(* Logix 5000 AddOnInstructionDefinition export POINT_DEC; software revision 30.00; part 2 of 3 *)

ADD_ON_INSTRUCTION B256_ADJ   (* revision 1.0 20170916, vendor Kenneth A. Fischer *)
// if c >= m then subtract m
// Revision note:
// Rev1.0: 20170916 - Initial Release
VAR_IN_OUT
   Inp_C : DINT[22]; {required}
END_VAR
VAR
   i : INT;
   j : INT;
END_VAR

ROUTINE Logic   (* ladder *)
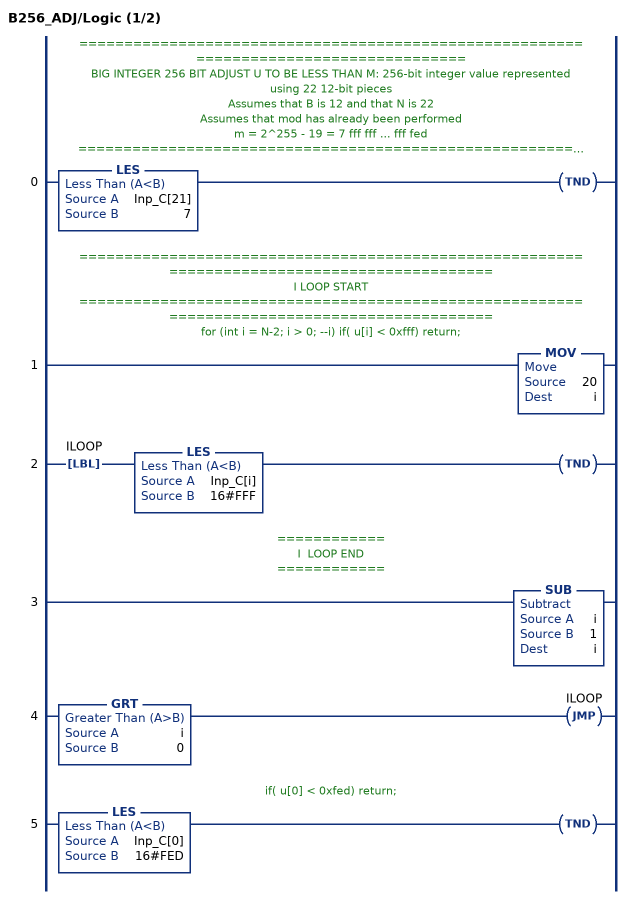
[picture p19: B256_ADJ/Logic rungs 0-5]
   // ======================================================================================
   // BIG INTEGER 256 BIT ADJUST U TO BE LESS THAN M: 256-bit integer value represented using 22 12-bit pieces
   // Assumes that B is 12 and that N is 22
   // Assumes that mod has already been performed
   // m = 2^255 - 19 = 7 fff fff ... fff fed
   // ======================================================================================
   // if (u[n-1] < 7) return;
   0: LES(Inp_C[21],7)TND();
   // ============================================================================================
   // I LOOP START
   // ============================================================================================
   // for (int i = N-2; i > 0; --i) if( u[i] < 0xfff) return;
   1: MOV(20,i);
   2: LBL(ILOOP)LES(Inp_C[i],16#FFF)TND();
   // ============
   // I  LOOP END
   // ============
   3: SUB(i,1,i);
   4: GRT(i,0)JMP(ILOOP);
   // if( u[0] < 0xfed) return;
   5: LES(Inp_C[0],16#FED)TND();
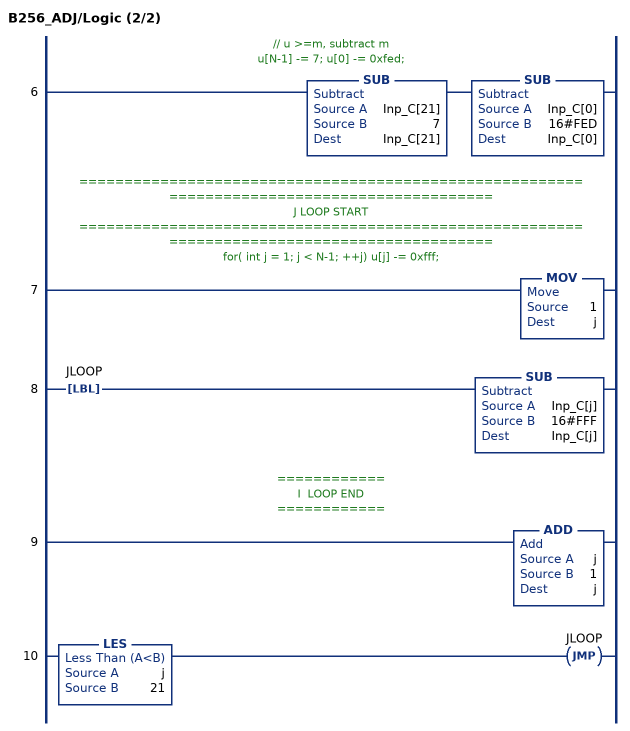
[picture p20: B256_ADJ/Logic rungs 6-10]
   // // u >=m, subtract m
   // u[N-1] -= 7; u[0] -= 0xfed;
   6: SUB(Inp_C[21],7,Inp_C[21])SUB(Inp_C[0],16#FED,Inp_C[0]);
   // ============================================================================================
   // J LOOP START
   // ============================================================================================
   // for( int j = 1; j < N-1; ++j) u[j] -= 0xfff;
   7: MOV(1,j);
   8: LBL(JLOOP)SUB(Inp_C[j],16#FFF,Inp_C[j]);
   // ============
   // I  LOOP END
   // ============
   9: ADD(j,1,j);
   10: LES(j,21)JMP(JLOOP);
END_ROUTINE
END_ADD_ON_INSTRUCTION

ADD_ON_INSTRUCTION B256_CtoE   (* revision 1.0 20170916, vendor Kenneth A. Fischer *)
// Convert 256-bit value using 22 12-bit pieces into 256-bit value using 32 8-bit pieces
// Revision note:
// Rev1.0: 20170916 - Initial Release
VAR_IN_OUT
   Inp_C : DINT[22]; {required}
   Out_E : DINT[32]; {required}
END_VAR
VAR
   i : INT;
   j : INT;
   TEMP1 : DINT;
   TEMP2 : DINT;
   D_SHL : D_SHL;
   D_SHR : D_SHR;
END_VAR

ROUTINE Logic   (* ladder *)
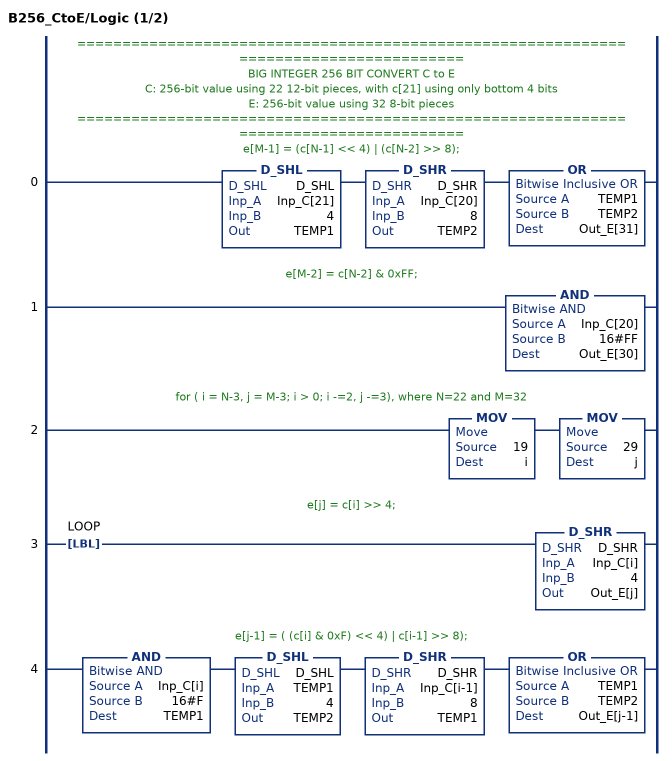
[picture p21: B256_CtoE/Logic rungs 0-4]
   // ======================================================================================
   // BIG INTEGER 256 BIT CONVERT C to E
   // C: 256-bit value using 22 12-bit pieces, with c[21] using only bottom 4 bits
   // E: 256-bit value using 32 8-bit pieces
   // ======================================================================================
   // e[M-1] = (c[N-1] << 4) | (c[N-2] >> 8);
   0: D_SHL(D_SHL,Inp_C[21],4,TEMP1)D_SHR(D_SHR,Inp_C[20],8,TEMP2)OR(TEMP1,TEMP2,Out_E[31]);
   // e[M-2] = c[N-2] & 0xFF;
   1: AND(Inp_C[20],16#FF,Out_E[30]);
   // for ( i = N-3, j = M-3; i > 0; i -=2, j -=3), where N=22 and M=32
   2: MOV(19,i)MOV(29,j);
   // e[j] = c[i] >> 4;
   3: LBL(LOOP)D_SHR(D_SHR,Inp_C[i],4,Out_E[j]);
   // e[j-1] = ( (c[i] & 0xF) << 4) | c[i-1] >> 8);
   4: AND(Inp_C[i],16#F,TEMP1)D_SHL(D_SHL,TEMP1,4,TEMP2)D_SHR(D_SHR,Inp_C[i-1],8,TEMP1)OR(TEMP1,TEMP2,Out_E[j-1]);
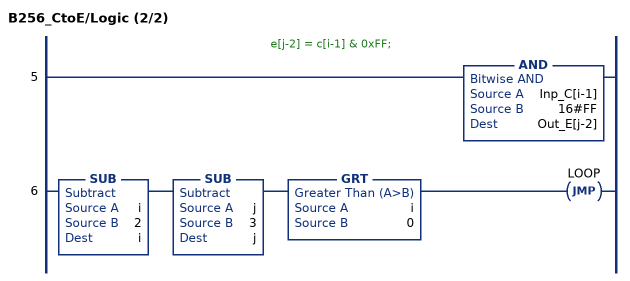
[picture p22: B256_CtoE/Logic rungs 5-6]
   // e[j-2] = c[i-1] & 0xFF;
   5: AND(Inp_C[i-1],16#FF,Out_E[j-2]);
   6: SUB(i,2,i)SUB(j,3,j)GRT(i,0)JMP(LOOP);
END_ROUTINE
END_ADD_ON_INSTRUCTION

ADD_ON_INSTRUCTION B256_EtoC   (* revision 1.0 20170916, vendor Kenneth A. Fischer *)
// Convert 256-bit value using 32 8-bit pieces into 256-bit value using 22 12-bit pieces
// Revision note:
// Rev1.0: 20170916 - Initial Release
VAR_IN_OUT
   Inp_E : DINT[32]; {required}
   Out_C : DINT[22]; {required}
END_VAR
VAR
   i : INT;
   j : INT;
   TEMP1 : DINT;
   TEMP2 : DINT;
   D_SHL : D_SHL;
   D_SHR : D_SHR;
END_VAR

ROUTINE Logic   (* ladder *)
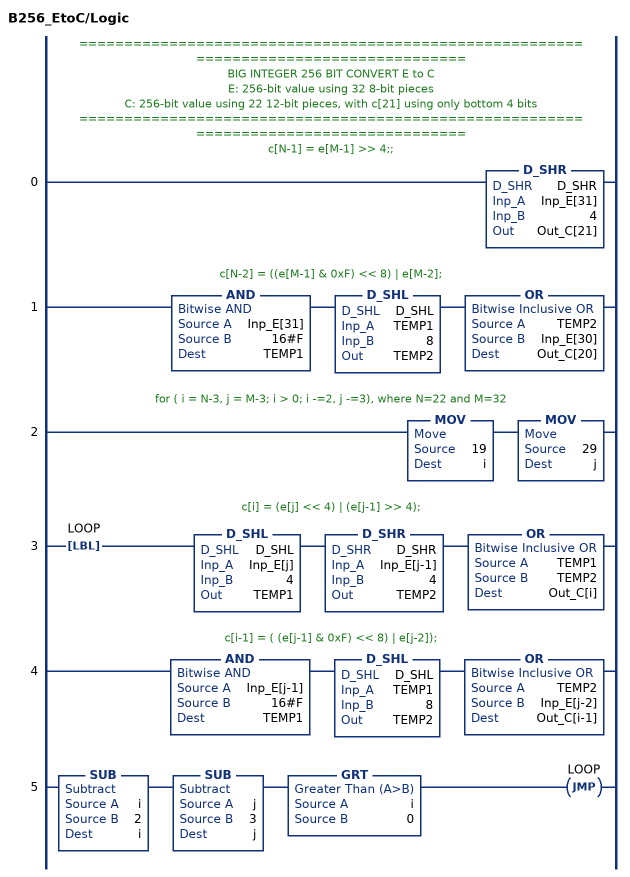
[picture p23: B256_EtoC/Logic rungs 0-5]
   // ======================================================================================
   // BIG INTEGER 256 BIT CONVERT E to C
   // E: 256-bit value using 32 8-bit pieces
   // C: 256-bit value using 22 12-bit pieces, with c[21] using only bottom 4 bits
   // ======================================================================================
   // c[N-1] = e[M-1] >> 4;;
   0: D_SHR(D_SHR,Inp_E[31],4,Out_C[21]);
   // c[N-2] = ((e[M-1] & 0xF) << 8) | e[M-2];
   1: AND(Inp_E[31],16#F,TEMP1)D_SHL(D_SHL,TEMP1,8,TEMP2)OR(TEMP2,Inp_E[30],Out_C[20]);
   // for ( i = N-3, j = M-3; i > 0; i -=2, j -=3), where N=22 and M=32
   2: MOV(19,i)MOV(29,j);
   // c[i] = (e[j] << 4) | (e[j-1] >> 4);
   3: LBL(LOOP)D_SHL(D_SHL,Inp_E[j],4,TEMP1)D_SHR(D_SHR,Inp_E[j-1],4,TEMP2)OR(TEMP1,TEMP2,Out_C[i]);
   // c[i-1] = ( (e[j-1] & 0xF) << 8) | e[j-2]);
   4: AND(Inp_E[j-1],16#F,TEMP1)D_SHL(D_SHL,TEMP1,8,TEMP2)OR(TEMP2,Inp_E[j-2],Out_C[i-1]);
   5: SUB(i,2,i)SUB(j,3,j)GRT(i,0)JMP(LOOP);
END_ROUTINE
END_ADD_ON_INSTRUCTION

ADD_ON_INSTRUCTION B256_COMPARE   (* revision 1.0 20170916, vendor Kenneth A. Fischer *)
// Determines if C1<C2, C1=C2, or C1>C2
// Revision note:
// Rev1.0: 20170916 - Initial Release
VAR_IN_OUT
   Inp_C1 : DINT[22]; {required}
   Inp_C2 : DINT[22]; {required}
END_VAR
VAR_OUTPUT
   EQUAL : BOOL; {access Read Only}
   GREATER : BOOL; {access Read Only}
   LESS : BOOL; {access Read Only}
END_VAR
VAR
   C3 : DINT;
   i : DINT;
END_VAR

ROUTINE Logic   (* ladder *)
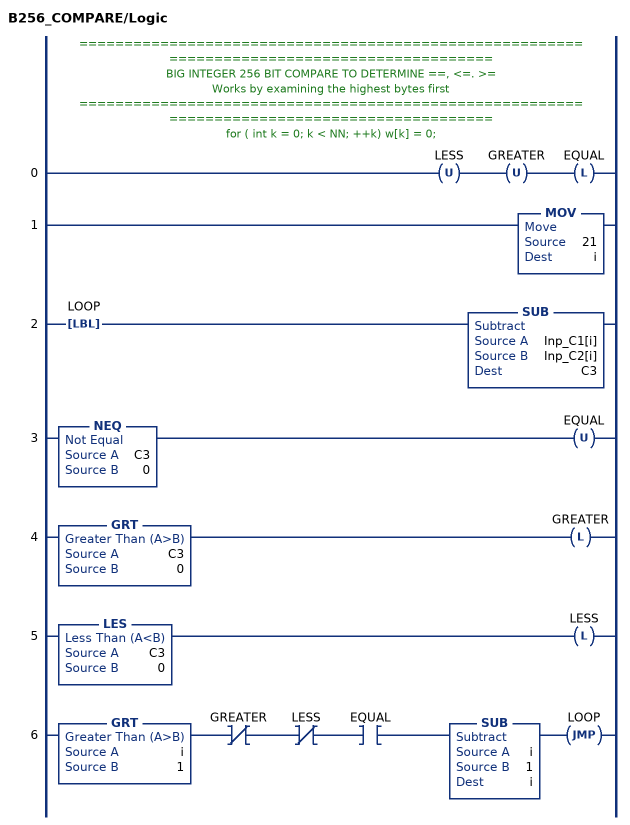
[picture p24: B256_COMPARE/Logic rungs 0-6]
   // ============================================================================================
   // BIG INTEGER 256 BIT COMPARE TO DETERMINE ==, <=. >=
   // Works by examining the highest bytes first
   // ============================================================================================
   // for ( int k = 0; k < NN; ++k) w[k] = 0;
   0: OTU(LESS)OTU(GREATER)OTL(EQUAL);
   1: MOV(21,i);
   2: LBL(LOOP)SUB(Inp_C1[i],Inp_C2[i],C3);
   3: NEQ(C3,0)OTU(EQUAL);
   4: GRT(C3,0)OTL(GREATER);
   5: LES(C3,0)OTL(LESS);
   6: GRT(i,1)XIO(GREATER)XIO(LESS)XIC(EQUAL)SUB(i,1,i)JMP(LOOP);
END_ROUTINE
END_ADD_ON_INSTRUCTION

ADD_ON_INSTRUCTION B256_StoC_LE   (* revision 1.0 20170916, vendor Kenneth A. Fischer *)
// Convert 256-bit value using 64 hex string characters into 256-bit value using 22 12-bit pieces
// Little Endian
// Revision note:
// Rev1.0: 20170916 - Initial Release
VAR_IN_OUT
   Temp_E : DINT[32]; {required}
   Inp_S : STRING; {required}
   Out_C : DINT[22]; {required}
END_VAR
VAR
   byte : DINT[3];
   D_SHL : D_SHL;
   i : INT;
   j : INT;
   k : DINT;
   temp : DINT;
   B256_CtoE : B256_CtoE;
   E : DINT[32];
   B256_EtoC : B256_EtoC;
END_VAR

ROUTINE Logic   (* ladder *)
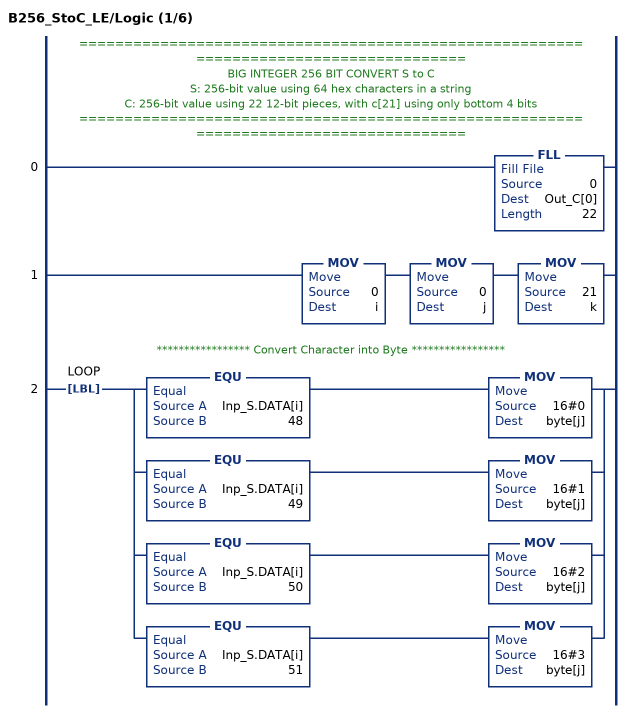
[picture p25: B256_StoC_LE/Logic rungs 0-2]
   // ======================================================================================
   // BIG INTEGER 256 BIT CONVERT S to C
   // S: 256-bit value using 64 hex characters in a string
   // C: 256-bit value using 22 12-bit pieces, with c[21] using only bottom 4 bits
   // ======================================================================================
   0: FLL(0,Out_C[0],22);
   1: MOV(0,i)MOV(0,j)MOV(21,k);
   // ***************** Convert Character into Byte *****************
   2: LBL(LOOP)[EQU(Inp_S.DATA[i],48) MOV(16#0,byte[j]) ,EQU(Inp_S.DATA[i],49) MOV(16#1,byte[j]) ,EQU(Inp_S.DATA[i],50) MOV(16#2,byte[j]) ,EQU(Inp_S.DATA[i],51) MOV(16#3,byte[j]) ];
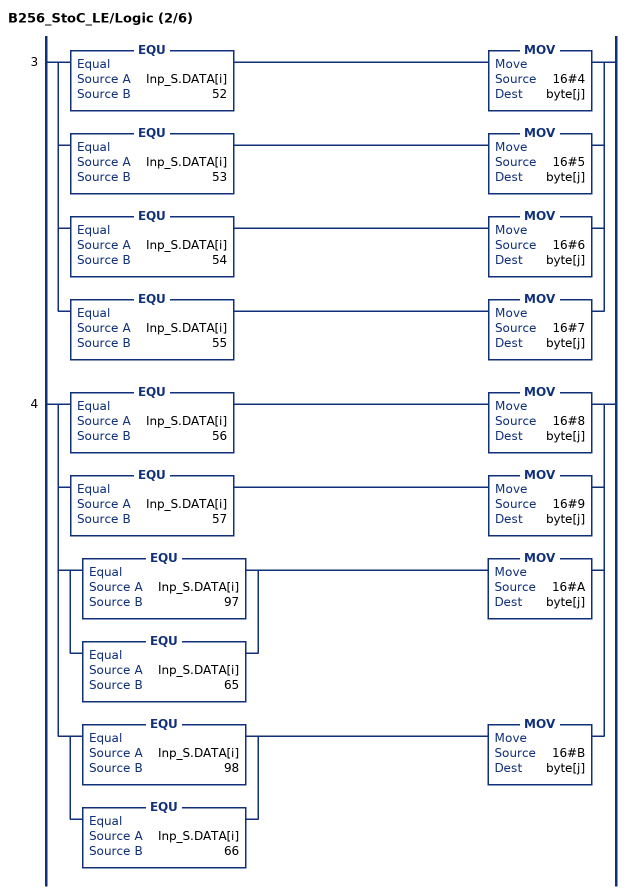
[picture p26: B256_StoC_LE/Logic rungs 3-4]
   3: [EQU(Inp_S.DATA[i],52) MOV(16#4,byte[j]) ,EQU(Inp_S.DATA[i],53) MOV(16#5,byte[j]) ,EQU(Inp_S.DATA[i],54) MOV(16#6,byte[j]) ,EQU(Inp_S.DATA[i],55) MOV(16#7,byte[j]) ];
   4: [EQU(Inp_S.DATA[i],56) MOV(16#8,byte[j]) ,EQU(Inp_S.DATA[i],57) MOV(16#9,byte[j]) ,[EQU(Inp_S.DATA[i],97) ,EQU(Inp_S.DATA[i],65) ] MOV(16#A,byte[j]) ,[EQU(Inp_S.DATA[i],98) ,EQU(Inp_S.DATA[i],66) ] MOV(16#B,byte[j]) ];
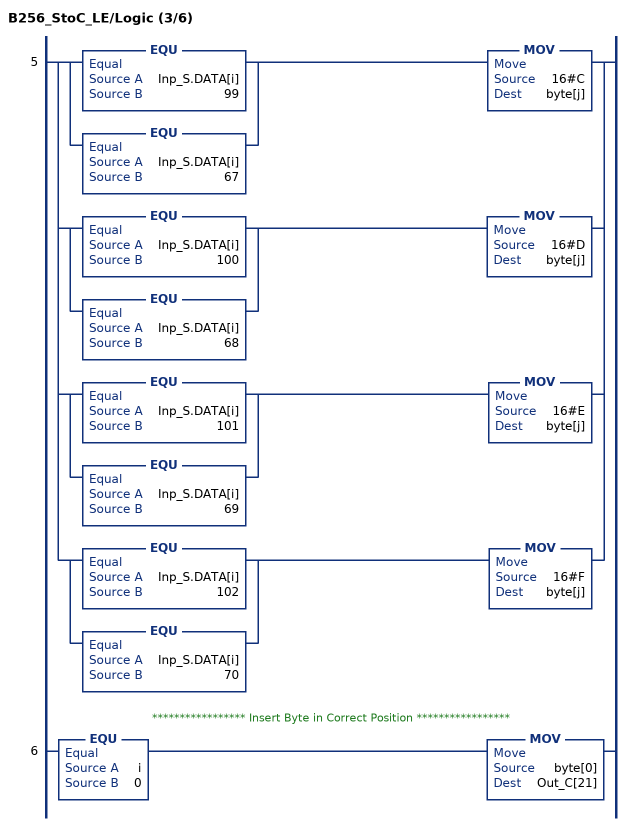
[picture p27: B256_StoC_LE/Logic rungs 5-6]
   5: [[EQU(Inp_S.DATA[i],99) ,EQU(Inp_S.DATA[i],67) ] MOV(16#C,byte[j]) ,[EQU(Inp_S.DATA[i],100) ,EQU(Inp_S.DATA[i],68) ] MOV(16#D,byte[j]) ,[EQU(Inp_S.DATA[i],101) ,EQU(Inp_S.DATA[i],69) ] MOV(16#E,byte[j]) ,[EQU(Inp_S.DATA[i],102) ,EQU(Inp_S.DATA[i],70) ] MOV(16#F,byte[j]) ];
   // ***************** Insert Byte in Correct Position *****************
   6: EQU(i,0)MOV(byte[0],Out_C[21]);
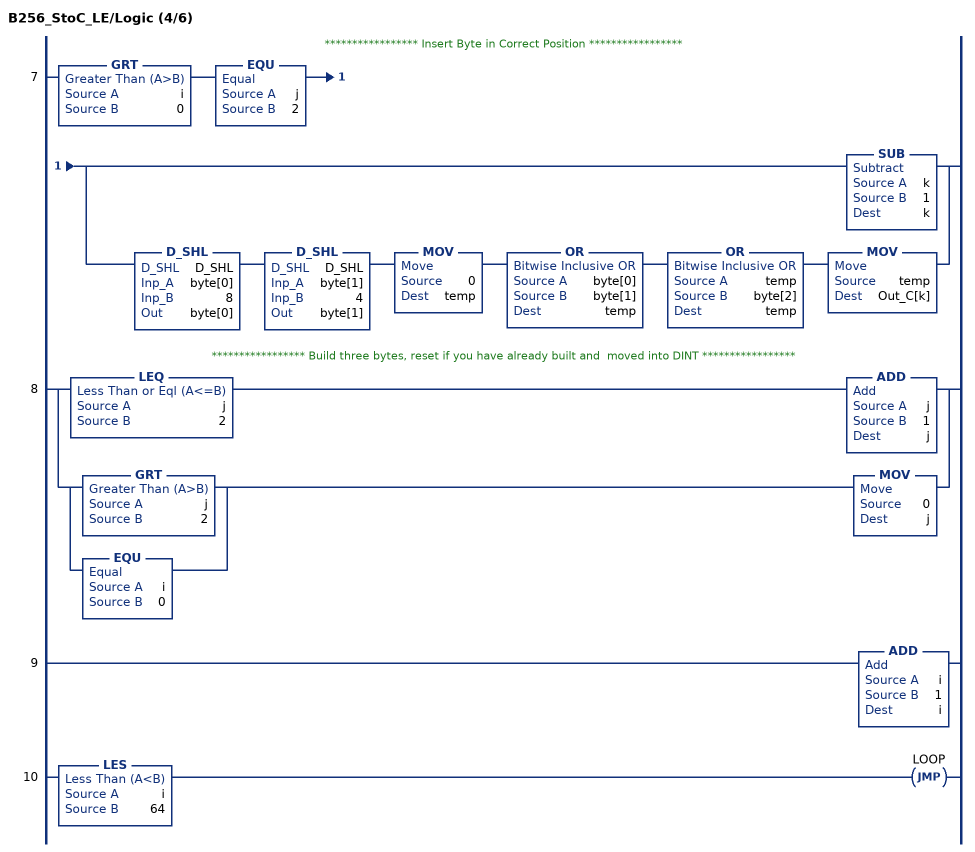
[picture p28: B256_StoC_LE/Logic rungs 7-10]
   // ***************** Insert Byte in Correct Position *****************
   7: GRT(i,0)EQU(j,2)[SUB(k,1,k) ,D_SHL(D_SHL,byte[0],8,byte[0]) D_SHL(D_SHL,byte[1],4,byte[1]) MOV(0,temp) OR(byte[0],byte[1],temp) OR(temp,byte[2],temp) MOV(temp,Out_C[k]) ];
   // ***************** Build three bytes, reset if you have already built and  moved into DINT *****************
   8: [LEQ(j,2) ADD(j,1,j) ,[GRT(j,2) ,EQU(i,0) ] MOV(0,j) ];
   9: ADD(i,1,i);
   10: LES(i,64)JMP(LOOP);
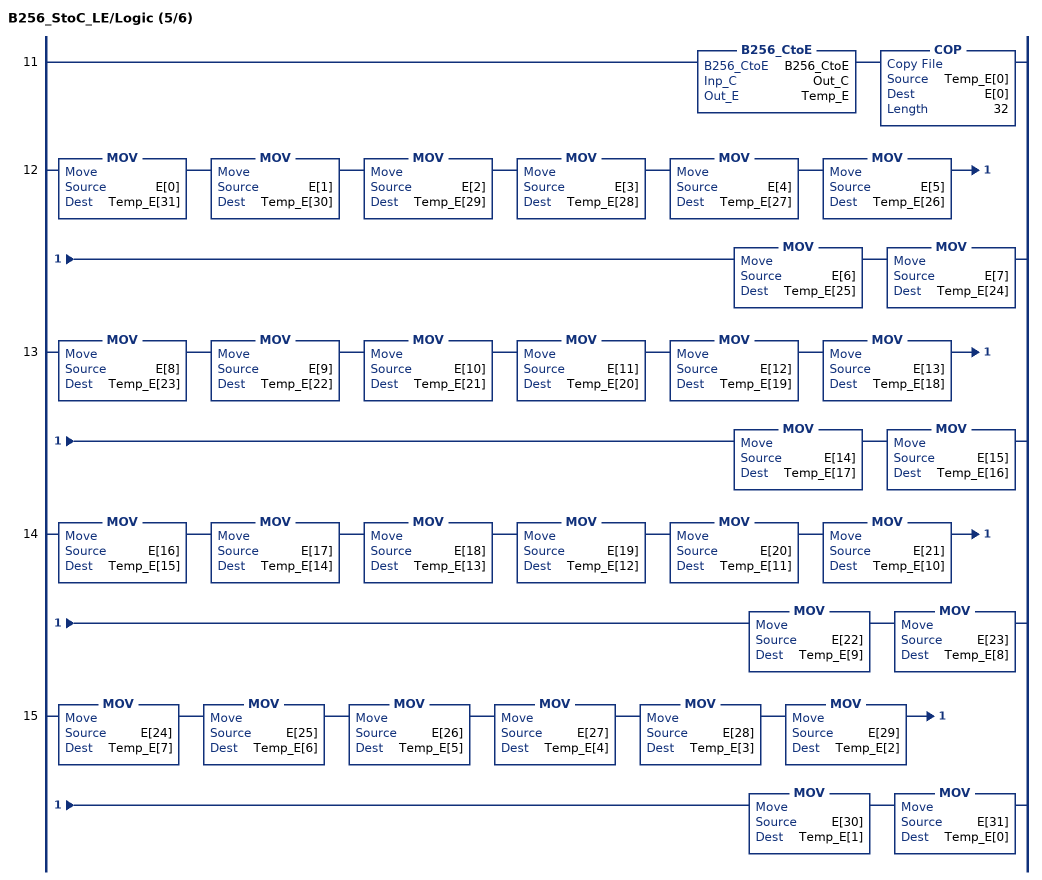
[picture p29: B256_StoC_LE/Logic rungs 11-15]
   11: B256_CtoE(B256_CtoE,Out_C,Temp_E)COP(Temp_E[0],E[0],32);
   12: MOV(E[0],Temp_E[31])MOV(E[1],Temp_E[30])MOV(E[2],Temp_E[29])MOV(E[3],Temp_E[28])MOV(E[4],Temp_E[27])MOV(E[5],Temp_E[26])MOV(E[6],Temp_E[25])MOV(E[7],Temp_E[24]);
   13: MOV(E[8],Temp_E[23])MOV(E[9],Temp_E[22])MOV(E[10],Temp_E[21])MOV(E[11],Temp_E[20])MOV(E[12],Temp_E[19])MOV(E[13],Temp_E[18])MOV(E[14],Temp_E[17])MOV(E[15],Temp_E[16]);
   14: MOV(E[16],Temp_E[15])MOV(E[17],Temp_E[14])MOV(E[18],Temp_E[13])MOV(E[19],Temp_E[12])MOV(E[20],Temp_E[11])MOV(E[21],Temp_E[10])MOV(E[22],Temp_E[9])MOV(E[23],Temp_E[8]);
   15: MOV(E[24],Temp_E[7])MOV(E[25],Temp_E[6])MOV(E[26],Temp_E[5])MOV(E[27],Temp_E[4])MOV(E[28],Temp_E[3])MOV(E[29],Temp_E[2])MOV(E[30],Temp_E[1])MOV(E[31],Temp_E[0]);
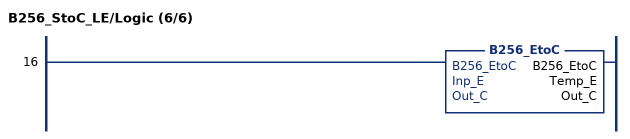
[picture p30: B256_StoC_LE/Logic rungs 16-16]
   16: B256_EtoC(B256_EtoC,Temp_E,Out_C);
END_ROUTINE
END_ADD_ON_INSTRUCTION

ADD_ON_INSTRUCTION B256_DEC   (* revision 1.0 20170916, vendor Kenneth A. Fischer *)
// c1 = --c1
// Revision note:
// Rev1.0: 20170916 - Initial Release
VAR_IN_OUT
   Inp_C : DINT[22]; {required}
END_VAR
VAR
   i : DINT;
END_VAR

ROUTINE Logic   (* ladder *)
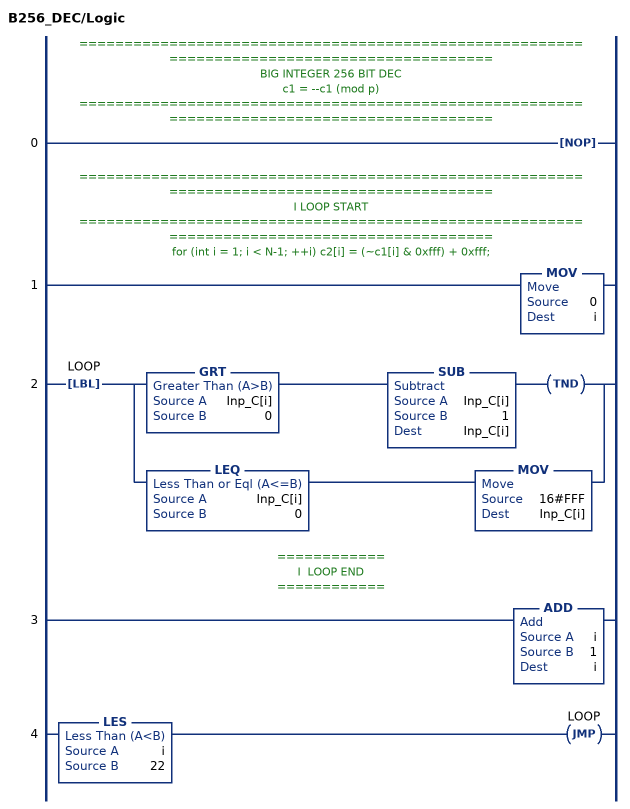
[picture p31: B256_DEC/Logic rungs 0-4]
   // ============================================================================================
   // BIG INTEGER 256 BIT DEC
   // c1 = --c1 (mod p)
   // ============================================================================================
   0: NOP();
   // ============================================================================================
   // I LOOP START
   // ============================================================================================
   // for (int i = 1; i < N-1; ++i) c2[i] = (~c1[i] & 0xfff) + 0xfff;
   1: MOV(0,i);
   2: LBL(LOOP)[GRT(Inp_C[i],0) SUB(Inp_C[i],1,Inp_C[i]) TND() ,LEQ(Inp_C[i],0) MOV(16#FFF,Inp_C[i]) ];
   // ============
   // I  LOOP END
   // ============
   3: ADD(i,1,i);
   4: LES(i,22)JMP(LOOP);
END_ROUTINE
END_ADD_ON_INSTRUCTION

ADD_ON_INSTRUCTION B256_MODPOW   (* revision 1.0 20170916, vendor Kenneth A. Fischer *)
// c2 = c1^e mod (2^255-19)
// Revision note:
// Rev1.0: 20170916 - Initial Release
VAR_IN_OUT
   Temp_C1 : DINT[22]; {required}
   Temp_C2 : DINT[22]; {required}
   Temp_D : DINT[43]; {required}
   Inp_C1 : DINT[22]; {required}   // V
   Inp_E : DINT[32]; {required}
   Out_C2 : DINT[22]; {required}   // U
END_VAR
VAR_OUTPUT
   i : INT; {access Read Only}
END_VAR
VAR_INPUT
   SEQCTRL_RESET : BOOL;   // Resets Point Multiplication if Toggled True
END_VAR
VAR_OUTPUT
   SEQCTRL_DN : BOOL; {access Read Only}   // Complete
   SEQCTRL_STEP : INT; {access Read Only}
END_VAR
VAR
   SEQCTRL_CMD : INT;
   SEQCTRL_DONE : INT;
   SEQCTRL_CMD_TABLE : INT[35];
   SEQCTRL_NEXT_STEP : INT;
   TEMP : INT;
   j : INT;
   b : DINT;
   B256_MUL : B256_MUL;
   B256_SQU : B256_SQU;
END_VAR

ROUTINE Logic   (* ladder *)
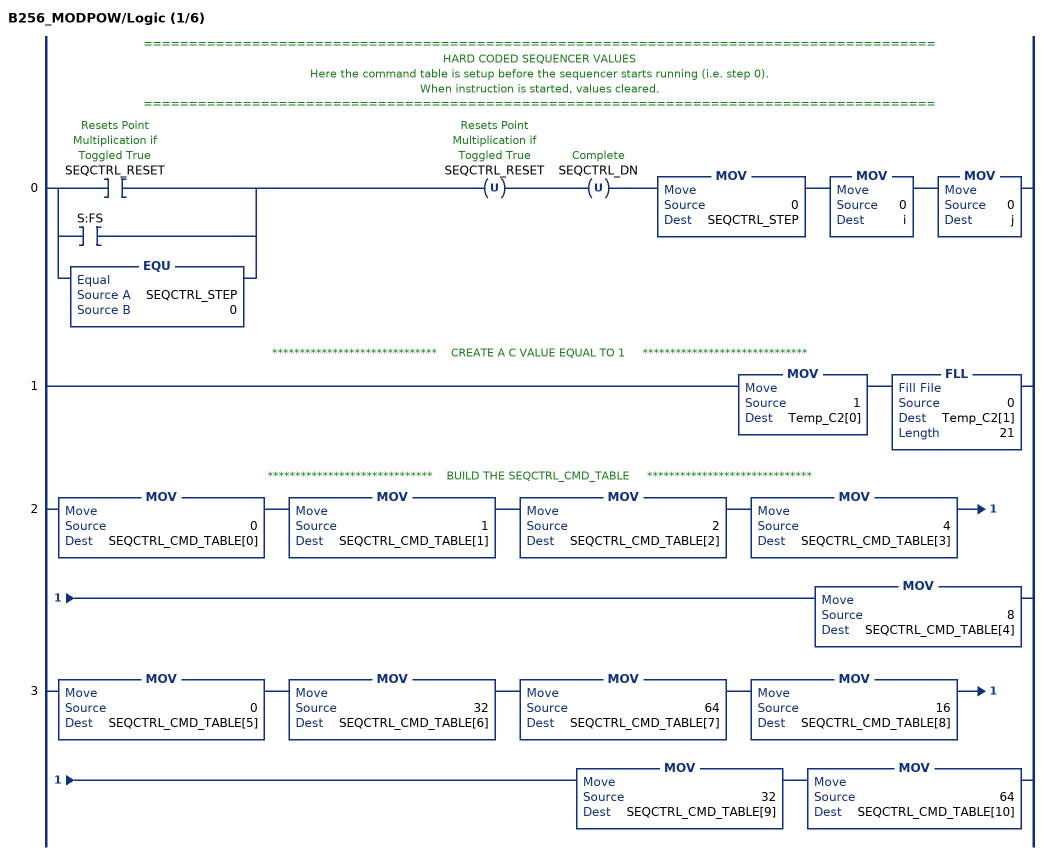
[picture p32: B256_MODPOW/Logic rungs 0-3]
   // ========================================================================================
   // HARD CODED SEQUENCER VALUES
   // Here the command table is setup before the sequencer starts running (i.e. step 0).
   // When instruction is started, values cleared.
   // ========================================================================================
   0: [[XIC(SEQCTRL_RESET) ,XIC(S:FS) ] ,EQU(SEQCTRL_STEP,0) ]OTU(SEQCTRL_RESET)OTU(SEQCTRL_DN)MOV(0,SEQCTRL_STEP)MOV(0,i)MOV(0,j);
   // ******************************    CREATE A C VALUE EQUAL TO 1     ******************************
   1: MOV(1,Temp_C2[0])FLL(0,Temp_C2[1],21);
   // ******************************    BUILD THE SEQCTRL_CMD_TABLE     ******************************
   2: MOV(0,SEQCTRL_CMD_TABLE[0])MOV(1,SEQCTRL_CMD_TABLE[1])MOV(2,SEQCTRL_CMD_TABLE[2])MOV(4,SEQCTRL_CMD_TABLE[3])MOV(8,SEQCTRL_CMD_TABLE[4]);
   3: MOV(0,SEQCTRL_CMD_TABLE[5])MOV(32,SEQCTRL_CMD_TABLE[6])MOV(64,SEQCTRL_CMD_TABLE[7])MOV(16,SEQCTRL_CMD_TABLE[8])MOV(32,SEQCTRL_CMD_TABLE[9])MOV(64,SEQCTRL_CMD_TABLE[10]);
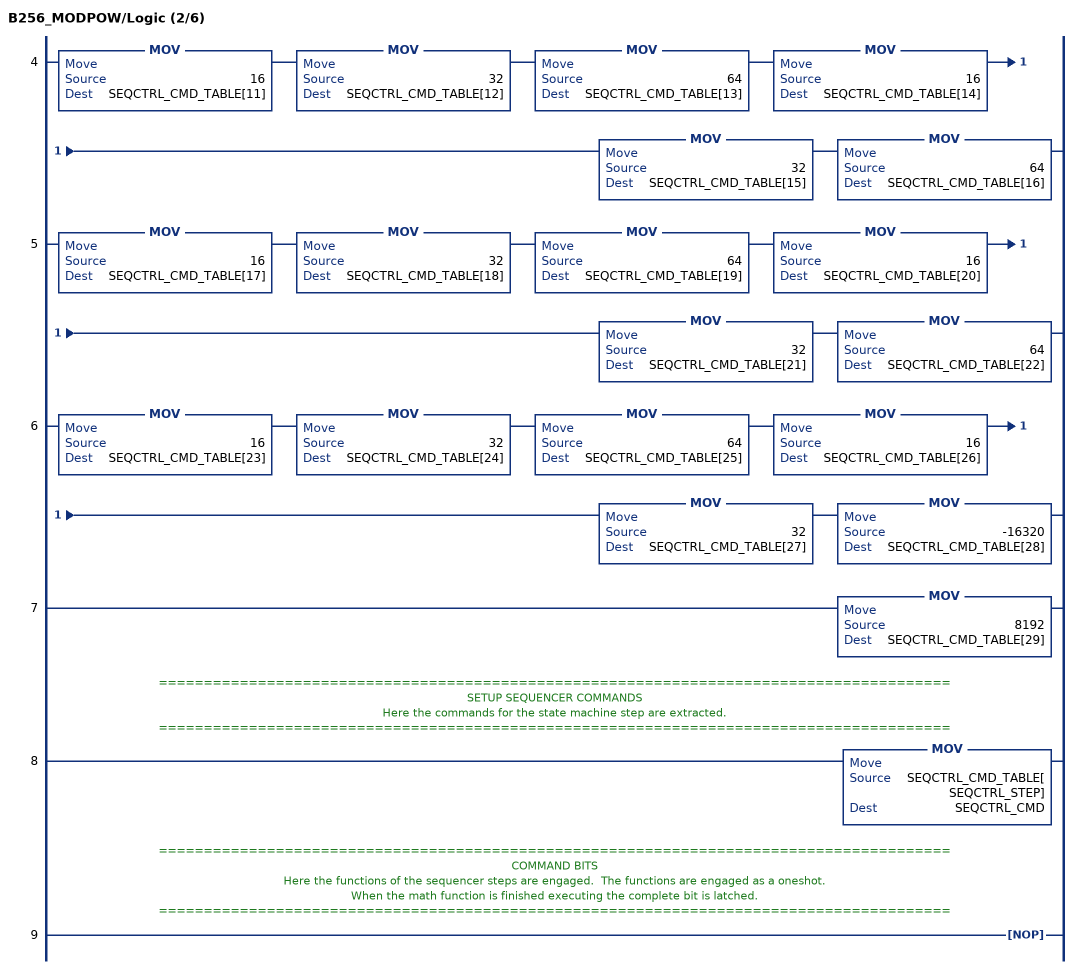
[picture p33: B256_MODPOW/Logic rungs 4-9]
   4: MOV(16,SEQCTRL_CMD_TABLE[11])MOV(32,SEQCTRL_CMD_TABLE[12])MOV(64,SEQCTRL_CMD_TABLE[13])MOV(16,SEQCTRL_CMD_TABLE[14])MOV(32,SEQCTRL_CMD_TABLE[15])MOV(64,SEQCTRL_CMD_TABLE[16]);
   5: MOV(16,SEQCTRL_CMD_TABLE[17])MOV(32,SEQCTRL_CMD_TABLE[18])MOV(64,SEQCTRL_CMD_TABLE[19])MOV(16,SEQCTRL_CMD_TABLE[20])MOV(32,SEQCTRL_CMD_TABLE[21])MOV(64,SEQCTRL_CMD_TABLE[22]);
   6: MOV(16,SEQCTRL_CMD_TABLE[23])MOV(32,SEQCTRL_CMD_TABLE[24])MOV(64,SEQCTRL_CMD_TABLE[25])MOV(16,SEQCTRL_CMD_TABLE[26])MOV(32,SEQCTRL_CMD_TABLE[27])MOV(-16320,SEQCTRL_CMD_TABLE[28]);
   7: MOV(8192,SEQCTRL_CMD_TABLE[29]);
   // ========================================================================================
   // SETUP SEQUENCER COMMANDS
   // Here the commands for the state machine step are extracted.
   // ========================================================================================
   8: MOV(SEQCTRL_CMD_TABLE[SEQCTRL_STEP],SEQCTRL_CMD);
   // ========================================================================================
   // COMMAND BITS
   // Here the functions of the sequencer steps are engaged.  The functions are engaged as a oneshot.
   // When the math function is finished executing the complete bit is latched.
   // ========================================================================================
   9: NOP();
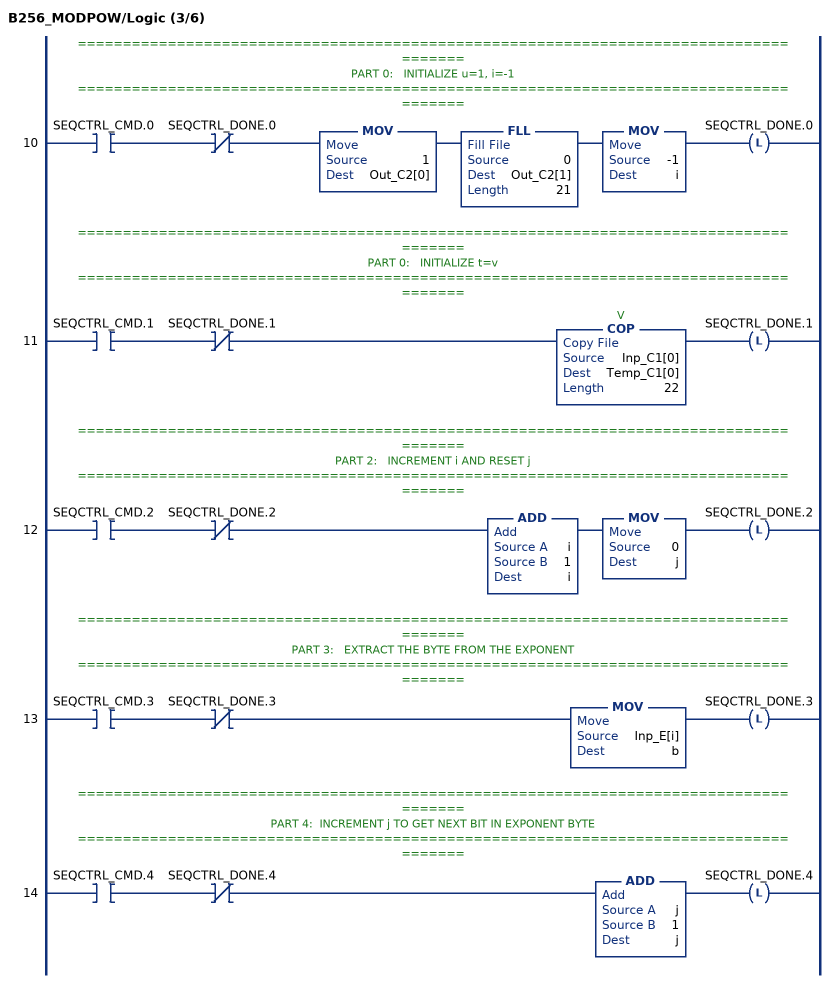
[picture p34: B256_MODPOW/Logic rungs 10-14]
   // ======================================================================================
   // PART 0:   INITIALIZE u=1, i=-1
   // ======================================================================================
   10: XIC(SEQCTRL_CMD.0)XIO(SEQCTRL_DONE.0)MOV(1,Out_C2[0])FLL(0,Out_C2[1],21)MOV(-1,i)OTL(SEQCTRL_DONE.0);
   // ======================================================================================
   // PART 0:   INITIALIZE t=v
   // ======================================================================================
   11: XIC(SEQCTRL_CMD.1)XIO(SEQCTRL_DONE.1)COP(Inp_C1[0],Temp_C1[0],22)OTL(SEQCTRL_DONE.1);
   // ======================================================================================
   // PART 2:   INCREMENT i AND RESET j
   // ======================================================================================
   12: XIC(SEQCTRL_CMD.2)XIO(SEQCTRL_DONE.2)ADD(i,1,i)MOV(0,j)OTL(SEQCTRL_DONE.2);
   // ======================================================================================
   // PART 3:   EXTRACT THE BYTE FROM THE EXPONENT
   // ======================================================================================
   13: XIC(SEQCTRL_CMD.3)XIO(SEQCTRL_DONE.3)MOV(Inp_E[i],b)OTL(SEQCTRL_DONE.3);
   // ======================================================================================
   // PART 4:  INCREMENT j TO GET NEXT BIT IN EXPONENT BYTE
   // ======================================================================================
   14: XIC(SEQCTRL_CMD.4)XIO(SEQCTRL_DONE.4)ADD(j,1,j)OTL(SEQCTRL_DONE.4);
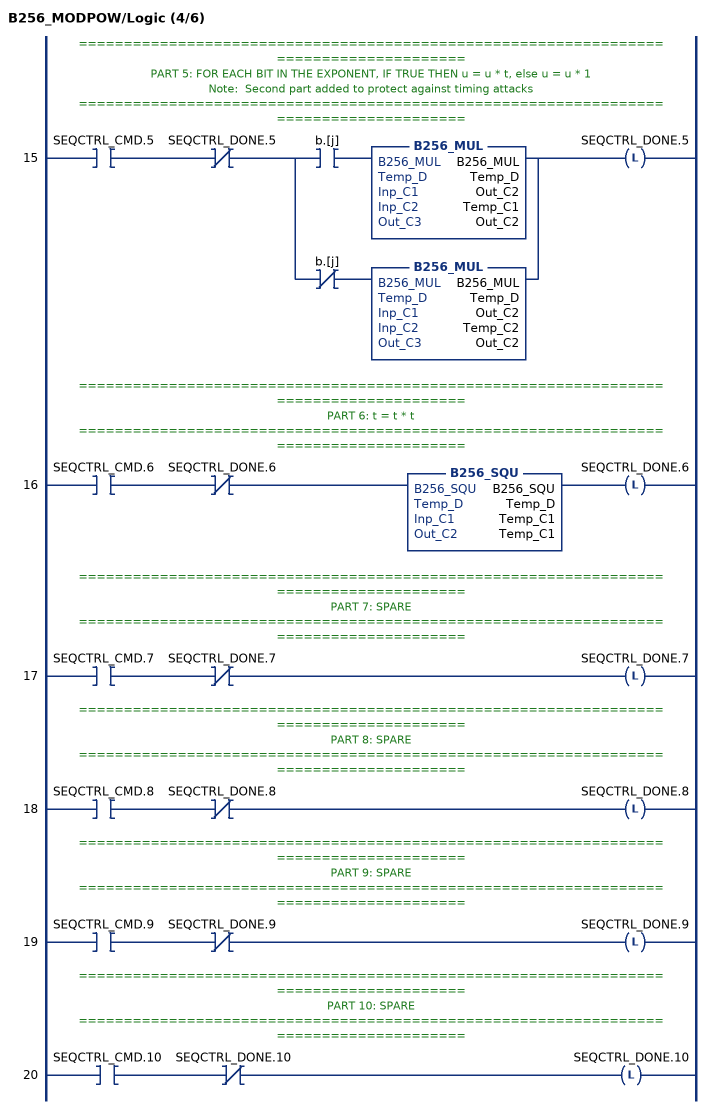
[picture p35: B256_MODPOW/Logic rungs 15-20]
   // ======================================================================================
   // PART 5: FOR EACH BIT IN THE EXPONENT, IF TRUE THEN u = u * t, else u = u * 1
   // Note:  Second part added to protect against timing attacks
   // ======================================================================================
   15: XIC(SEQCTRL_CMD.5)XIO(SEQCTRL_DONE.5)[XIC(b.[j]) B256_MUL(B256_MUL,Temp_D,Out_C2,Temp_C1,Out_C2) ,XIO(b.[j]) B256_MUL(B256_MUL,Temp_D,Out_C2,Temp_C2,Out_C2) ]OTL(SEQCTRL_DONE.5);
   // ======================================================================================
   // PART 6: t = t * t
   // ======================================================================================
   16: XIC(SEQCTRL_CMD.6)XIO(SEQCTRL_DONE.6)B256_SQU(B256_SQU,Temp_D,Temp_C1,Temp_C1)OTL(SEQCTRL_DONE.6);
   // ======================================================================================
   // PART 7: SPARE
   // ======================================================================================
   17: XIC(SEQCTRL_CMD.7)XIO(SEQCTRL_DONE.7)OTL(SEQCTRL_DONE.7);
   // ======================================================================================
   // PART 8: SPARE
   // ======================================================================================
   18: XIC(SEQCTRL_CMD.8)XIO(SEQCTRL_DONE.8)OTL(SEQCTRL_DONE.8);
   // ======================================================================================
   // PART 9: SPARE
   // ======================================================================================
   19: XIC(SEQCTRL_CMD.9)XIO(SEQCTRL_DONE.9)OTL(SEQCTRL_DONE.9);
   // ======================================================================================
   // PART 10: SPARE
   // ======================================================================================
   20: XIC(SEQCTRL_CMD.10)XIO(SEQCTRL_DONE.10)OTL(SEQCTRL_DONE.10);
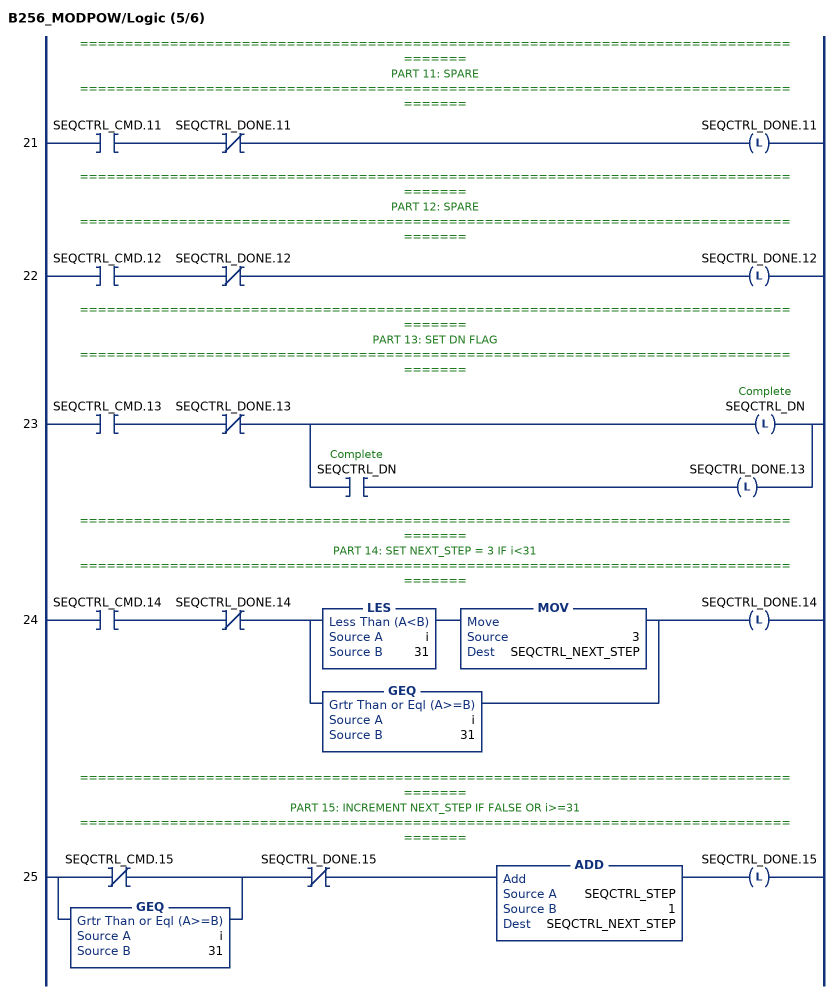
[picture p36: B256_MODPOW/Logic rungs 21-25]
   // ======================================================================================
   // PART 11: SPARE
   // ======================================================================================
   21: XIC(SEQCTRL_CMD.11)XIO(SEQCTRL_DONE.11)OTL(SEQCTRL_DONE.11);
   // ======================================================================================
   // PART 12: SPARE
   // ======================================================================================
   22: XIC(SEQCTRL_CMD.12)XIO(SEQCTRL_DONE.12)OTL(SEQCTRL_DONE.12);
   // ======================================================================================
   // PART 13: SET DN FLAG
   // ======================================================================================
   23: XIC(SEQCTRL_CMD.13)XIO(SEQCTRL_DONE.13)[OTL(SEQCTRL_DN) ,XIC(SEQCTRL_DN) OTL(SEQCTRL_DONE.13) ];
   // ======================================================================================
   // PART 14: SET NEXT_STEP = 3 IF i<31
   // ======================================================================================
   24: XIC(SEQCTRL_CMD.14)XIO(SEQCTRL_DONE.14)[LES(i,31) MOV(3,SEQCTRL_NEXT_STEP) ,GEQ(i,31) ]OTL(SEQCTRL_DONE.14);
   // ======================================================================================
   // PART 15: INCREMENT NEXT_STEP IF FALSE OR i>=31
   // ======================================================================================
   25: [XIO(SEQCTRL_CMD.15) ,GEQ(i,31) ]XIO(SEQCTRL_DONE.15)ADD(SEQCTRL_STEP,1,SEQCTRL_NEXT_STEP)OTL(SEQCTRL_DONE.15);
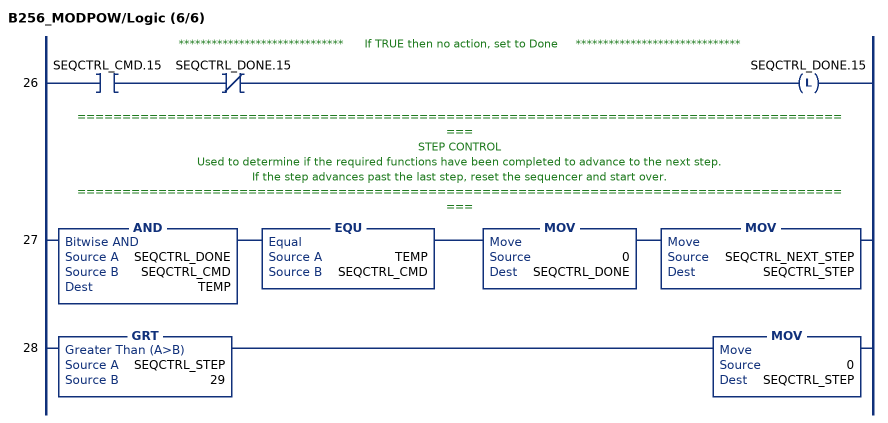
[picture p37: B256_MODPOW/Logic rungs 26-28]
   // ******************************      If TRUE then no action, set to Done     ******************************
   26: XIC(SEQCTRL_CMD.15)XIO(SEQCTRL_DONE.15)OTL(SEQCTRL_DONE.15);
   // ========================================================================================
   // STEP CONTROL
   // Used to determine if the required functions have been completed to advance to the next step.
   // If the step advances past the last step, reset the sequencer and start over.
   // ========================================================================================
   27: AND(SEQCTRL_DONE,SEQCTRL_CMD,TEMP)EQU(TEMP,SEQCTRL_CMD)MOV(0,SEQCTRL_DONE)MOV(SEQCTRL_NEXT_STEP,SEQCTRL_STEP);
   28: GRT(SEQCTRL_STEP,29)MOV(0,SEQCTRL_STEP);
END_ROUTINE
END_ADD_ON_INSTRUCTION
